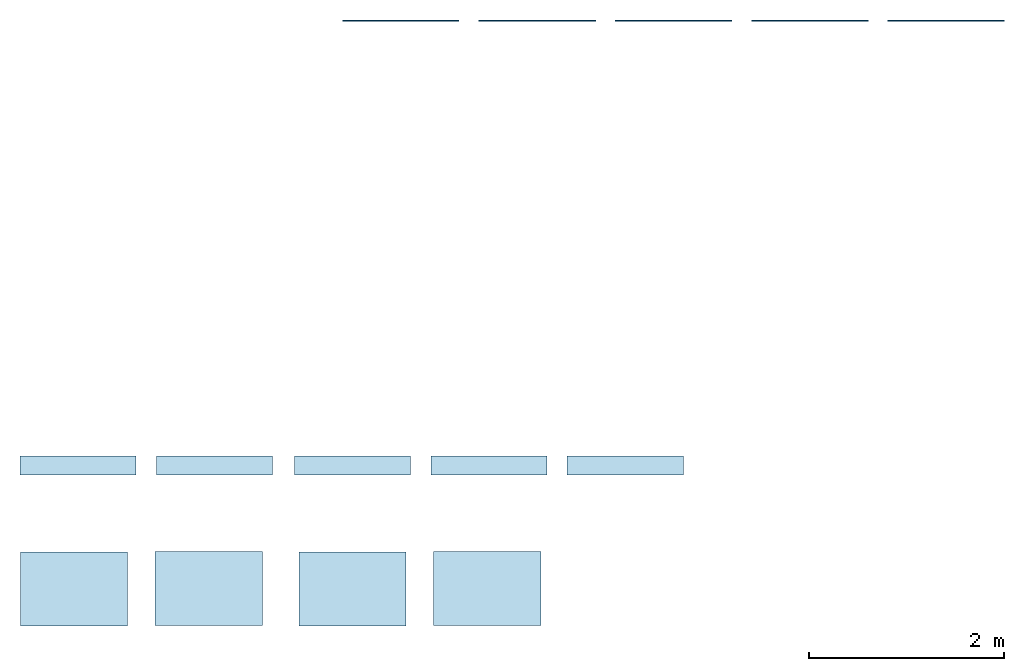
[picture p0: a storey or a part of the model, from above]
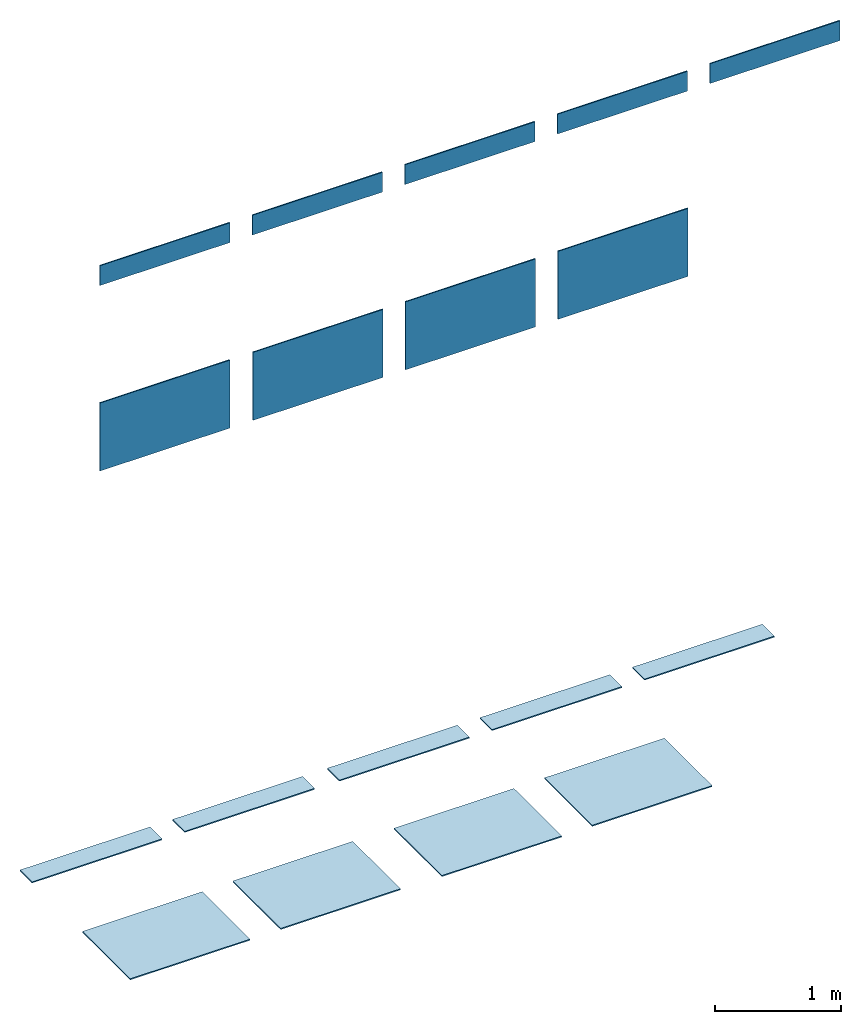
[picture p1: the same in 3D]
Properties of the parts of a building model (IFC2X3)

# File
Description: ViewDefinition [CoordinationView_V2.0]
File name: Número de proyecto
Time: 2017-10-19T16:40:05
Written by: The EXPRESS Data Manager Version 5.02.0100.07 : 28 Aug 2013
Made in: 20160225_1515(x64) - Exporter 17.0.416.0 - Alternate UI 17.12.14.0
Comment: STEP Physical File produced by: The EXPRESS Data Manager Version 5.02.0100.07 : 28 Aug 2013 * Module: EDMstepFileFactory/EDMstandAlone * Creation date: Thu Oct 19 16:40:05 2017 * Host: REVIT * Database: C:\Users\corte\AppData\Local\Temp\{14164174-3DCD-4E05-B68C-632851972AA7}\ifc * Database version: 5507 * Database creation date: Thu Oct 19 16:40:02 2017 * Schema: IFC2X3 * Model: DataRepository.ifc * Model creation date: Thu Oct 19 16:40:03 2017 * Header model: DataRepository.ifc_HeaderModel * Header model creation date: Thu Oct 19 16:40:03 2017 * EDMuser: sdai-user * EDMgroup: sdai-group * License ID and type: 5605 : Permanent license. Expiry date: * EDMstepFileFactory options: 020000

# IfcProject, Número de proyecto
LongName: Nombre de proyecto; Phase: Estado de proyecto

# IfcSite, Default
RefLatitude: 40, 25, 0, 86975; RefLongitude: -3, -42, -1, -243858; RefElevation: 0 m

# IfcBuilding
Pset_BuildingCommon - NumberOfStoreys: 1

# IfcBuildingStorey, WORLD WOODS FLOOR TILES
LongName: WORLD WOODS FLOOR TILES; Elevation: 0 m

# IfcSlab: Suelo:VIVES ADAMANT FREMONT NATURAL 22x38, Suelo:VIVES ADAMANT FREMONT NATURAL 22x38:195481
In: WORLD WOODS FLOOR TILES
PredefinedType: FLOOR; Material: VIVES ADAMANT FREMONT NATURAL 22x38 0.011 m
Pset_SlabCommon - IsExternal: no; LoadBearing: yes; PitchAngle: 0 deg; Reference: VIVES ADAMANT FREMONT NATURAL 22x38; ThermalTransmittance: 136.364 kg/K/s3
Pset_ManufacturerTypeInformation - Manufacturer: VIVES Azulejos y Gres S.A.

# IfcSlab: Suelo:VIVES ADAMANT NORDLAND BEIGE 22x38, Suelo:VIVES ADAMANT NORDLAND BEIGE 22x38:195333
In: WORLD WOODS FLOOR TILES
PredefinedType: FLOOR; Material: VIVES ADAMANT NORDLAND BEIGE 22x38 0.011 m
Pset_SlabCommon - IsExternal: no; LoadBearing: yes; PitchAngle: 0 deg; Reference: VIVES ADAMANT NORDLAND BEIGE 22x38; ThermalTransmittance: 136.364 kg/K/s3
Pset_ManufacturerTypeInformation - Manufacturer: VIVES Azulejos y Gres S.A.

# IfcSlab: Suelo:VIVES ADAMANT OKINAWA CARBÓN 22x38, Suelo:VIVES ADAMANT OKINAWA CARBÓN 22x38:198033
In: WORLD WOODS FLOOR TILES
PredefinedType: FLOOR; Material: VIVES ADAMANT OKINAWA CARBON 22x38 0.011 m
Pset_SlabCommon - IsExternal: no; LoadBearing: yes; PitchAngle: 0 deg; Reference: VIVES ADAMANT OKINAWA CARBÓN 22x38; ThermalTransmittance: 136.364 kg/K/s3
Pset_ManufacturerTypeInformation - Manufacturer: VIVES Azulejos y Gres S.A.

# IfcSlab: Suelo:VIVES ADAMANT VENETO CANELA 22x38, Suelo:VIVES ADAMANT VENETO CANELA 22x38:198025
In: WORLD WOODS FLOOR TILES
PredefinedType: FLOOR; Material: VIVES ADAMANT VENETO CANELA 22x38 0.011 m
Pset_SlabCommon - IsExternal: no; LoadBearing: yes; PitchAngle: 0 deg; Reference: VIVES ADAMANT VENETO CANELA 22x38; ThermalTransmittance: 136.364 kg/K/s3
Pset_ManufacturerTypeInformation - Manufacturer: VIVES Azulejos y Gres S.A.

# IfcSlab: Suelo:VIVES FREMONT-R NATURAL 19.2x119.3, Suelo:VIVES FREMONT-R NATURAL 19.2x119.3:195081
In: WORLD WOODS FLOOR TILES
PredefinedType: FLOOR; Material: VIVES FREMONT-R NATURAL 19.2x119.3 0.011 m
Pset_SlabCommon - IsExternal: no; LoadBearing: yes; PitchAngle: 0 deg; Reference: VIVES FREMONT-R NATURAL 19.2x119.3; ThermalTransmittance: 136.364 kg/K/s3
Pset_ManufacturerTypeInformation - Manufacturer: VIVES Azulejos y Gres S.A.

# IfcSlab: Suelo:VIVES NAMIBE-R 19.2x119.3, Suelo:VIVES NAMIBE-R 19.2x119.3:195267
In: WORLD WOODS FLOOR TILES
PredefinedType: FLOOR; Material: VIVES NAMIBE-R 19.2x119.3 0.011 m
Pset_SlabCommon - IsExternal: no; LoadBearing: yes; PitchAngle: 0 deg; Reference: VIVES NAMIBE-R 19.2x119.3; ThermalTransmittance: 136.364 kg/K/s3
Pset_ManufacturerTypeInformation - Manufacturer: VIVES Azulejos y Gres S.A.

# IfcSlab: Suelo:VIVES NORDLAND-R BEIGE 19.2x119.3, Suelo:VIVES NORDLAND-R BEIGE 19.2x119.3:189750
In: WORLD WOODS FLOOR TILES
PredefinedType: FLOOR; Material: VIVES NORDLAND-R BEIGE 19.2x119.3 0.011 m
Pset_SlabCommon - Reference: VIVES NORDLAND-R BEIGE 19.2x119.3; IsExternal: no; LoadBearing: yes; ThermalTransmittance: 136.364 kg/K/s3; PitchAngle: 0 deg
Pset_ManufacturerTypeInformation - Manufacturer: VIVES Azulejos y Gres S.A.

# IfcSlab: Suelo:VIVES OKINAWA-R CARBON 19.2x119.3, Suelo:VIVES OKINAWA-R CARBON 19.2x119.3:195199
In: WORLD WOODS FLOOR TILES
PredefinedType: FLOOR; Material: VIVES OKINAWA-R CARBON 19.2x119.3 0.011 m
Pset_SlabCommon - IsExternal: no; LoadBearing: yes; PitchAngle: 0 deg; Reference: VIVES OKINAWA-R CARBON 19.2x119.3; ThermalTransmittance: 136.364 kg/K/s3
Pset_ManufacturerTypeInformation - Manufacturer: VIVES Azulejos y Gres S.A.

# IfcSlab: Suelo:VIVES VENETO-R CANELA 19.2x119.3, Suelo:VIVES VENETO-R CANELA 19.2x119.3:195148
In: WORLD WOODS FLOOR TILES
PredefinedType: FLOOR; Material: VIVES VENETO-R CANELA 19.2x119.3 0.011 m
Pset_SlabCommon - IsExternal: no; LoadBearing: yes; PitchAngle: 0 deg; Reference: VIVES VENETO-R CANELA 19.2x119.3; ThermalTransmittance: 136.364 kg/K/s3
Pset_ManufacturerTypeInformation - Manufacturer: VIVES Azulejos y Gres S.A.

# IfcWallStandardCase: Muro básico:VIVES ADAMANT FREMONT NATURAL 22x38, Muro básico:VIVES ADAMANT FREMONT NATURAL 22x38:196440
In: WORLD WOODS FLOOR TILES
Type - PredefinedType: STANDARD; Material: VIVES ADAMANT FREMONT NATURAL 22x38 0.011 m
Pset_WallCommon - IsExternal: no; LoadBearing: no; ExtendToStructure: no; Reference: VIVES ADAMANT FREMONT NATURAL 22x38; ThermalTransmittance: 136.364 kg/K/s3
Pset_ManufacturerTypeInformation - Manufacturer: VIVES Azulejos y Gres S.A.

# IfcWallStandardCase: Muro básico:VIVES ADAMANT NORDLAND BEIGE 22x38, Muro básico:VIVES ADAMANT NORDLAND BEIGE 22x38:196212
In: WORLD WOODS FLOOR TILES
Type - PredefinedType: STANDARD; Material: VIVES ADAMANT NORDLAND BEIGE 22x38 0.011 m
Pset_WallCommon - IsExternal: no; LoadBearing: no; ExtendToStructure: no; Reference: VIVES ADAMANT NORDLAND BEIGE 22x38; ThermalTransmittance: 136.364 kg/K/s3
Pset_ManufacturerTypeInformation - Manufacturer: VIVES Azulejos y Gres S.A.

# IfcWallStandardCase: Muro básico:VIVES ADAMANT OKINAWA CARBON 22x38, Muro básico:VIVES ADAMANT OKINAWA CARBON 22x38:196634
In: WORLD WOODS FLOOR TILES
Type - PredefinedType: STANDARD; Material: VIVES ADAMANT OKINAWA CARBON 22x38 0.011 m
Pset_WallCommon - IsExternal: no; LoadBearing: no; ExtendToStructure: no; Reference: VIVES ADAMANT OKINAWA CARBON 22x38; ThermalTransmittance: 136.364 kg/K/s3
Pset_ManufacturerTypeInformation - Manufacturer: VIVES Azulejos y Gres S.A.

# IfcWallStandardCase: Muro básico:VIVES ADAMANT VENETO CANELA 22x38, Muro básico:VIVES ADAMANT VENETO CANELA 22x38:196536
In: WORLD WOODS FLOOR TILES
Type - PredefinedType: STANDARD; Material: VIVES ADAMANT VENETO CANELA 22x38 0.011 m
Pset_WallCommon - IsExternal: no; LoadBearing: no; ExtendToStructure: no; Reference: VIVES ADAMANT VENETO CANELA 22x38; ThermalTransmittance: 136.364 kg/K/s3
Pset_ManufacturerTypeInformation - Manufacturer: VIVES Azulejos y Gres S.A.

# IfcWallStandardCase: Muro básico:VIVES FREMONT-R NATURAL 19.2x119.3, Muro básico:VIVES FREMONT-R NATURAL 19.2x119.3:195807
In: WORLD WOODS FLOOR TILES
Type - PredefinedType: STANDARD; Material: VIVES FREMONT-R NATURAL 19.2x119.3 0.011 m
Pset_WallCommon - IsExternal: no; LoadBearing: no; ExtendToStructure: no; Reference: VIVES FREMONT-R NATURAL 19.2x119.3; ThermalTransmittance: 136.364 kg/K/s3
Pset_ManufacturerTypeInformation - Manufacturer: VIVES Azulejos y Gres S.A.

# IfcWallStandardCase: Muro básico:VIVES NAMIBE-R 19.2x119.3, Muro básico:VIVES NAMIBE-R 19.2x119.3:196107
In: WORLD WOODS FLOOR TILES
Type - PredefinedType: STANDARD; Material: VIVES NAMIBE-R 19.2x119.3 0.011 m
Pset_WallCommon - IsExternal: no; LoadBearing: no; ExtendToStructure: no; Reference: VIVES NAMIBE-R 19.2x119.3; ThermalTransmittance: 136.364 kg/K/s3
Pset_ManufacturerTypeInformation - Manufacturer: VIVES Azulejos y Gres S.A.

# IfcWallStandardCase: Muro básico:VIVES NORDLAND-R BEIGE 19.2x119.3, Muro básico:VIVES NORDLAND-R BEIGE 19.2x119.3:190692
In: WORLD WOODS FLOOR TILES
Type - PredefinedType: STANDARD; Material: VIVES NORDLAND-R BEIGE 19.2x119.3 0.011 m
Pset_WallCommon - Reference: VIVES NORDLAND-R BEIGE 19.2x119.3; IsExternal: no; LoadBearing: no; ExtendToStructure: no; ThermalTransmittance: 136.364 kg/K/s3
Pset_ManufacturerTypeInformation - Manufacturer: VIVES Azulejos y Gres S.A.

# IfcWallStandardCase: Muro básico:VIVES OKINAWA-R CARBON 19.2x119.3, Muro básico:VIVES OKINAWA-R CARBON 19.2x119.3:196013
In: WORLD WOODS FLOOR TILES
Type - PredefinedType: STANDARD; Material: VIVES OKINAWA-R CARBON 19.2x119.3 0.011 m
Pset_WallCommon - IsExternal: no; LoadBearing: no; ExtendToStructure: no; Reference: VIVES OKINAWA-R CARBON 19.2x119.3; ThermalTransmittance: 136.364 kg/K/s3
Pset_ManufacturerTypeInformation - Manufacturer: VIVES Azulejos y Gres S.A.

# IfcWallStandardCase: Muro básico:VIVES VENETO-R CANELA 19.2x119.3, Muro básico:VIVES VENETO-R CANELA 19.2x119.3:195905
In: WORLD WOODS FLOOR TILES
Type - PredefinedType: STANDARD; Material: VIVES VENETO-R CANELA 19.2x119.3 0.011 m
Pset_WallCommon - IsExternal: no; LoadBearing: no; ExtendToStructure: no; Reference: VIVES VENETO-R CANELA 19.2x119.3; ThermalTransmittance: 136.364 kg/K/s3
Pset_ManufacturerTypeInformation - Manufacturer: VIVES Azulejos y Gres S.A.
